VERSION 5.8 ;
BUSBITCHARS "[]" ;
DIVIDERCHAR "/" ;
UNITS
    DATABASE MICRONS 1000 ;
END UNITS

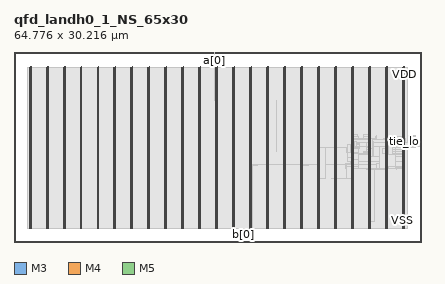
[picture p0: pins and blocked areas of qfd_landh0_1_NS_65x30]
MACRO qfd_landh0_1_NS_65x30
  FOREIGN qfd_landh0_1_NS_65x30 0 0 ;
  CLASS BLOCK ;
  SIZE 64.776 BY 30.216 ;
  PIN a[0]
    DIRECTION INPUT ;
    USE SIGNAL ;
    PORT
      LAYER M3 ;
        RECT  31.86 30.179 31.878 30.216 ;
    END
  END a[0]
  PIN b[0]
    DIRECTION OUTPUT ;
    USE SIGNAL ;
    PORT
      LAYER M3 ;
        RECT  36.54 0 36.558 0.037 ;
    END
  END b[0]
  PIN ck
    DIRECTION INPUT ;
    USE SIGNAL ;
    PORT
      LAYER M4 ;
        RECT  64.692 15.12 64.776 15.144 ;
    END
  END ck
  PIN ck_s
    DIRECTION INPUT ;
    USE SIGNAL ;
    PORT
      LAYER M4 ;
        RECT  64.692 15.216 64.776 15.24 ;
    END
  END ck_s
  PIN en
    DIRECTION INPUT ;
    USE SIGNAL ;
    PORT
      LAYER M4 ;
        RECT  64.692 15.312 64.776 15.336 ;
    END
  END en
  PIN fault
    DIRECTION OUTPUT ;
    USE SIGNAL ;
    PORT
      LAYER M4 ;
        RECT  64.692 15.408 64.776 15.432 ;
    END
  END fault
  PIN k0
    DIRECTION INPUT ;
    USE SIGNAL ;
    PORT
      LAYER M4 ;
        RECT  64.692 15.504 64.776 15.528 ;
    END
  END k0
  PIN k1
    DIRECTION INPUT ;
    USE SIGNAL ;
    PORT
      LAYER M4 ;
        RECT  64.692 15.6 64.776 15.624 ;
    END
  END k1
  PIN k2
    DIRECTION INPUT ;
    USE SIGNAL ;
    PORT
      LAYER M4 ;
        RECT  64.692 15.696 64.776 15.72 ;
    END
  END k2
  PIN rs
    DIRECTION INPUT ;
    USE SIGNAL ;
    PORT
      LAYER M4 ;
        RECT  64.692 15.792 64.776 15.816 ;
    END
  END rs
  PIN tie_hi
    DIRECTION OUTPUT ;
    USE SIGNAL ;
    PORT
      LAYER M4 ;
        RECT  64.692 15.888 64.776 15.912 ;
    END
  END tie_hi
  PIN tie_lo
    DIRECTION OUTPUT ;
    USE SIGNAL ;
    PORT
      LAYER M4 ;
        RECT  64.692 15.984 64.776 16.008 ;
    END
  END tie_lo
  PIN VDD
    DIRECTION INOUT ;
    USE POWER ;
    PORT
      LAYER M5 ;
        RECT  61.992 2.151 62.112 27.833 ;
        RECT  59.292 2.151 59.412 27.833 ;
        RECT  56.592 2.151 56.712 27.833 ;
        RECT  53.892 2.151 54.012 27.833 ;
        RECT  51.192 2.151 51.312 27.833 ;
        RECT  48.492 2.151 48.612 27.833 ;
        RECT  45.792 2.151 45.912 27.833 ;
        RECT  43.092 2.151 43.212 27.833 ;
        RECT  40.392 2.151 40.512 27.833 ;
        RECT  37.692 2.151 37.812 27.833 ;
        RECT  34.992 2.151 35.112 27.833 ;
        RECT  32.292 2.151 32.412 27.833 ;
        RECT  29.592 2.151 29.712 27.833 ;
        RECT  26.892 2.151 27.012 27.833 ;
        RECT  24.192 2.151 24.312 27.833 ;
        RECT  21.492 2.151 21.612 27.833 ;
        RECT  18.792 2.151 18.912 27.833 ;
        RECT  16.092 2.151 16.212 27.833 ;
        RECT  13.392 2.151 13.512 27.833 ;
        RECT  10.692 2.151 10.812 27.833 ;
        RECT  7.992 2.151 8.112 27.833 ;
        RECT  5.292 2.151 5.412 27.833 ;
        RECT  2.592 2.151 2.712 27.833 ;
    END
  END VDD
  PIN VSS
    DIRECTION INOUT ;
    USE GROUND ;
    PORT
      LAYER M5 ;
        RECT  61.8 2.137 61.92 27.819 ;
        RECT  59.1 2.137 59.22 27.819 ;
        RECT  56.4 2.137 56.52 27.819 ;
        RECT  53.7 2.137 53.82 27.819 ;
        RECT  51 2.137 51.12 27.819 ;
        RECT  48.3 2.137 48.42 27.819 ;
        RECT  45.6 2.137 45.72 27.819 ;
        RECT  42.9 2.137 43.02 27.819 ;
        RECT  40.2 2.137 40.32 27.819 ;
        RECT  37.5 2.137 37.62 27.819 ;
        RECT  34.8 2.137 34.92 27.819 ;
        RECT  32.1 2.137 32.22 27.819 ;
        RECT  29.4 2.137 29.52 27.819 ;
        RECT  26.7 2.137 26.82 27.819 ;
        RECT  24 2.137 24.12 27.819 ;
        RECT  21.3 2.137 21.42 27.819 ;
        RECT  18.6 2.137 18.72 27.819 ;
        RECT  15.9 2.137 16.02 27.819 ;
        RECT  13.2 2.137 13.32 27.819 ;
        RECT  10.5 2.137 10.62 27.819 ;
        RECT  7.8 2.137 7.92 27.819 ;
        RECT  5.1 2.137 5.22 27.819 ;
        RECT  2.4 2.137 2.52 27.819 ;
    END
  END VSS
  OBS
    LAYER RVTN ;
     RECT  2.16 2.16 62.586 2.295 ;
     RECT  2.16 2.565 62.586 2.835 ;
     RECT  2.16 3.105 62.586 3.375 ;
     RECT  2.16 3.645 62.586 3.915 ;
     RECT  2.16 4.185 62.586 4.455 ;
     RECT  2.16 4.725 62.586 4.995 ;
     RECT  2.16 5.265 62.586 5.535 ;
     RECT  2.16 5.805 62.586 6.075 ;
     RECT  2.16 6.345 62.586 6.615 ;
     RECT  2.16 6.885 62.586 7.155 ;
     RECT  2.16 7.425 62.586 7.695 ;
     RECT  2.16 7.965 62.586 8.235 ;
     RECT  2.16 8.505 62.586 8.775 ;
     RECT  2.16 9.045 62.586 9.315 ;
     RECT  2.16 9.585 62.586 9.855 ;
     RECT  2.16 10.125 62.586 10.395 ;
     RECT  2.16 10.665 62.586 10.935 ;
     RECT  2.16 11.205 62.586 11.475 ;
     RECT  2.16 11.745 62.586 12.015 ;
     RECT  2.16 12.285 62.586 12.555 ;
     RECT  2.16 12.825 62.586 13.095 ;
     RECT  2.16 13.365 62.586 13.635 ;
     RECT  2.16 13.905 62.586 14.175 ;
     RECT  2.16 14.445 62.586 14.715 ;
     RECT  2.16 14.985 62.586 15.255 ;
     RECT  2.16 15.525 62.586 15.795 ;
     RECT  2.16 16.065 62.586 16.335 ;
     RECT  2.16 16.605 62.586 16.875 ;
     RECT  2.16 17.145 62.586 17.415 ;
     RECT  2.16 17.685 62.586 17.955 ;
     RECT  2.16 18.225 62.586 18.495 ;
     RECT  2.16 18.765 62.586 19.035 ;
     RECT  2.16 19.305 62.586 19.575 ;
     RECT  2.16 19.845 62.586 20.115 ;
     RECT  2.16 20.385 62.586 20.655 ;
     RECT  2.16 20.925 62.586 21.195 ;
     RECT  2.16 21.465 62.586 21.735 ;
     RECT  2.16 22.005 62.586 22.275 ;
     RECT  2.16 22.545 62.586 22.815 ;
     RECT  2.16 23.085 62.586 23.355 ;
     RECT  2.16 23.625 62.586 23.895 ;
     RECT  2.16 24.165 62.586 24.435 ;
     RECT  2.16 24.705 62.586 24.975 ;
     RECT  2.16 25.245 62.586 25.515 ;
     RECT  2.16 25.785 62.586 26.055 ;
     RECT  2.16 26.325 62.586 26.595 ;
     RECT  2.16 26.865 62.586 27.135 ;
     RECT  2.16 27.405 62.586 27.675 ;
    LAYER RVTP ;
     RECT  2.16 2.295 62.586 2.565 ;
     RECT  2.16 2.835 62.586 3.105 ;
     RECT  2.16 3.375 62.586 3.645 ;
     RECT  2.16 3.915 62.586 4.185 ;
     RECT  2.16 4.455 62.586 4.725 ;
     RECT  2.16 4.995 62.586 5.265 ;
     RECT  2.16 5.535 62.586 5.805 ;
     RECT  2.16 6.075 62.586 6.345 ;
     RECT  2.16 6.615 62.586 6.885 ;
     RECT  2.16 7.155 62.586 7.425 ;
     RECT  2.16 7.695 62.586 7.965 ;
     RECT  2.16 8.235 62.586 8.505 ;
     RECT  2.16 8.775 62.586 9.045 ;
     RECT  2.16 9.315 62.586 9.585 ;
     RECT  2.16 9.855 62.586 10.125 ;
     RECT  2.16 10.395 62.586 10.665 ;
     RECT  2.16 10.935 62.586 11.205 ;
     RECT  2.16 11.475 62.586 11.745 ;
     RECT  2.16 12.015 62.586 12.285 ;
     RECT  2.16 12.555 62.586 12.825 ;
     RECT  2.16 13.095 62.586 13.365 ;
     RECT  2.16 13.635 62.586 13.905 ;
     RECT  2.16 14.175 62.586 14.445 ;
     RECT  2.16 14.715 62.586 14.985 ;
     RECT  2.16 15.255 62.586 15.525 ;
     RECT  2.16 15.795 62.586 16.065 ;
     RECT  2.16 16.335 62.586 16.605 ;
     RECT  2.16 16.875 62.586 17.145 ;
     RECT  2.16 17.415 62.586 17.685 ;
     RECT  2.16 17.955 62.586 18.225 ;
     RECT  2.16 18.495 62.586 18.765 ;
     RECT  2.16 19.035 62.586 19.305 ;
     RECT  2.16 19.575 62.586 19.845 ;
     RECT  2.16 20.115 62.586 20.385 ;
     RECT  2.16 20.655 62.586 20.925 ;
     RECT  2.16 21.195 62.586 21.465 ;
     RECT  2.16 21.735 62.586 22.005 ;
     RECT  2.16 22.275 62.586 22.545 ;
     RECT  2.16 22.815 62.586 23.085 ;
     RECT  2.16 23.355 62.586 23.625 ;
     RECT  2.16 23.895 62.586 24.165 ;
     RECT  2.16 24.435 62.586 24.705 ;
     RECT  2.16 24.975 62.586 25.245 ;
     RECT  2.16 25.515 62.586 25.785 ;
     RECT  2.16 26.055 62.586 26.325 ;
     RECT  2.16 26.595 62.586 26.865 ;
     RECT  2.16 27.135 62.586 27.405 ;
     RECT  2.16 27.675 62.586 27.81 ;
    LAYER M1 ;
     RECT  2.16 2.151 62.586 27.819 ;
    LAYER M2 ;
     RECT  36.535 0.531 37.859 0.549 ;
     RECT  2.16 2.151 62.586 27.819 ;
     RECT  62.586 14.958 63.311 16.092 ;
     RECT  63.311 14.958 63.347 16.02 ;
     RECT  63.347 14.958 63.887 15.552 ;
     RECT  62.586 16.848 63.887 16.866 ;
     RECT  63.887 14.958 63.923 14.976 ;
    LAYER M3 ;
     RECT  36.54 0.012 36.558 0.554 ;
     RECT  37.836 0.526 37.854 2.143 ;
     RECT  2.415 2.143 2.505 2.413 ;
     RECT  5.115 2.143 5.205 2.413 ;
     RECT  7.815 2.143 7.905 2.413 ;
     RECT  10.515 2.143 10.605 2.413 ;
     RECT  13.215 2.143 13.305 2.413 ;
     RECT  15.915 2.143 16.005 2.413 ;
     RECT  18.615 2.143 18.705 2.413 ;
     RECT  21.315 2.143 21.405 2.413 ;
     RECT  24.015 2.143 24.105 2.413 ;
     RECT  26.715 2.143 26.805 2.413 ;
     RECT  29.415 2.143 29.505 2.413 ;
     RECT  32.115 2.143 32.205 2.413 ;
     RECT  34.815 2.143 34.905 2.413 ;
     RECT  40.215 2.143 40.305 2.413 ;
     RECT  42.915 2.143 43.005 2.413 ;
     RECT  45.615 2.143 45.705 2.413 ;
     RECT  48.315 2.143 48.405 2.413 ;
     RECT  51.015 2.143 51.105 2.413 ;
     RECT  53.715 2.143 53.805 2.413 ;
     RECT  56.415 2.143 56.505 2.413 ;
     RECT  59.115 2.143 59.205 2.413 ;
     RECT  61.815 2.143 61.905 2.413 ;
     RECT  38.844 3.181 38.862 3.299 ;
     RECT  56.415 2.413 56.697 3.307 ;
     RECT  37.515 2.143 37.854 3.343 ;
     RECT  37.515 3.343 37.89 3.389 ;
     RECT  51.015 2.413 51.297 10.021 ;
     RECT  50.544 10.021 51.297 10.121 ;
     RECT  49.428 10.165 49.446 10.205 ;
     RECT  59.115 2.413 59.397 11.479 ;
     RECT  56.415 3.307 57.402 11.515 ;
     RECT  56.088 11.515 57.402 11.551 ;
     RECT  58.14 11.479 59.397 11.551 ;
     RECT  53.715 2.413 53.997 11.641 ;
     RECT  60.804 11.479 60.822 11.641 ;
     RECT  53.715 11.641 54.234 11.659 ;
     RECT  56.088 11.551 59.397 11.677 ;
     RECT  60.588 11.641 60.822 11.677 ;
     RECT  61.815 2.413 62.097 11.677 ;
     RECT  60.588 11.677 62.097 11.713 ;
     RECT  55.944 11.677 59.634 11.749 ;
     RECT  60.444 11.713 62.097 11.749 ;
     RECT  53.1 11.659 54.234 11.785 ;
     RECT  55.944 11.749 62.097 11.785 ;
     RECT  53.1 11.785 54.666 11.821 ;
     RECT  55.548 11.785 62.097 11.821 ;
     RECT  53.1 11.821 62.097 11.975 ;
     RECT  45.615 2.413 45.897 12.187 ;
     RECT  52.776 12.235 52.794 12.283 ;
     RECT  38.772 12.187 38.79 12.317 ;
     RECT  45.615 12.187 45.99 12.317 ;
     RECT  46.764 12.187 46.782 12.317 ;
     RECT  52.668 12.283 52.794 12.413 ;
     RECT  53.568 11.975 62.097 12.865 ;
     RECT  53.064 12.865 62.097 13.981 ;
     RECT  52.992 13.981 62.097 14.009 ;
     RECT  52.992 14.009 54.774 14.203 ;
     RECT  52.848 14.203 54.774 14.243 ;
     RECT  55.584 14.009 62.097 14.405 ;
     RECT  56.016 14.405 62.097 14.755 ;
     RECT  53.532 14.243 54.774 14.791 ;
     RECT  53.532 14.791 54.954 15.019 ;
     RECT  56.016 14.755 62.37 15.053 ;
     RECT  63.9 14.953 63.918 15.223 ;
     RECT  63.864 15.223 63.918 15.295 ;
     RECT  53.028 15.019 54.954 15.449 ;
     RECT  53.604 15.449 54.954 15.629 ;
     RECT  63.288 15.295 63.918 15.725 ;
     RECT  56.052 15.053 62.37 15.787 ;
     RECT  63.288 15.725 63.882 15.787 ;
     RECT  53.715 15.629 54.954 15.799 ;
     RECT  56.052 15.787 63.882 15.799 ;
     RECT  53.715 15.799 63.882 15.863 ;
     RECT  63.288 15.863 63.882 16.097 ;
     RECT  53.715 15.863 62.298 16.295 ;
     RECT  58.716 16.295 62.298 16.403 ;
     RECT  53.715 16.295 57.654 16.529 ;
     RECT  59.115 16.403 62.298 16.529 ;
     RECT  59.115 16.529 62.097 16.601 ;
     RECT  60.66 16.601 62.097 16.709 ;
     RECT  53.715 16.529 54.81 16.799 ;
     RECT  55.584 16.529 56.697 16.799 ;
     RECT  57.492 16.529 57.654 16.799 ;
     RECT  60.66 16.709 60.678 16.799 ;
     RECT  63.864 16.097 63.882 16.871 ;
     RECT  57.636 16.799 57.654 16.943 ;
     RECT  53.715 16.799 54.666 17.069 ;
     RECT  55.62 16.799 56.697 17.069 ;
     RECT  41.724 14.377 41.742 22.469 ;
     RECT  32.115 2.413 32.397 22.477 ;
     RECT  2.415 2.413 2.697 27.557 ;
     RECT  5.115 2.413 5.397 27.557 ;
     RECT  7.815 2.413 8.097 27.557 ;
     RECT  10.515 2.413 10.797 27.557 ;
     RECT  13.215 2.413 13.497 27.557 ;
     RECT  15.915 2.413 16.197 27.557 ;
     RECT  18.615 2.413 18.897 27.557 ;
     RECT  21.315 2.413 21.597 27.557 ;
     RECT  24.015 2.413 24.297 27.557 ;
     RECT  26.715 2.413 26.997 27.557 ;
     RECT  29.415 2.413 29.697 27.557 ;
     RECT  34.815 2.413 35.097 27.557 ;
     RECT  37.515 3.389 37.797 27.557 ;
     RECT  40.215 2.413 40.497 27.557 ;
     RECT  42.915 2.413 43.197 27.557 ;
     RECT  45.615 12.317 45.897 27.557 ;
     RECT  48.315 2.413 48.597 27.557 ;
     RECT  51.015 10.121 51.297 27.557 ;
     RECT  53.715 17.069 53.997 27.557 ;
     RECT  56.415 17.069 56.697 27.557 ;
     RECT  59.115 16.601 59.397 27.557 ;
     RECT  61.815 16.709 62.097 27.557 ;
     RECT  2.607 27.557 2.697 27.827 ;
     RECT  5.307 27.557 5.397 27.827 ;
     RECT  8.007 27.557 8.097 27.827 ;
     RECT  10.707 27.557 10.797 27.827 ;
     RECT  13.407 27.557 13.497 27.827 ;
     RECT  16.107 27.557 16.197 27.827 ;
     RECT  18.807 27.557 18.897 27.827 ;
     RECT  21.507 27.557 21.597 27.827 ;
     RECT  24.207 27.557 24.297 27.827 ;
     RECT  26.907 27.557 26.997 27.827 ;
     RECT  29.607 27.557 29.697 27.827 ;
     RECT  31.86 22.477 32.397 27.827 ;
     RECT  35.007 27.557 35.097 27.827 ;
     RECT  37.707 27.557 37.797 27.827 ;
     RECT  40.407 27.557 40.497 27.827 ;
     RECT  43.107 27.557 43.197 27.827 ;
     RECT  45.807 27.557 45.897 27.827 ;
     RECT  48.507 27.557 48.597 27.827 ;
     RECT  51.207 27.557 51.297 27.827 ;
     RECT  53.907 27.557 53.997 27.827 ;
     RECT  56.607 27.557 56.697 27.827 ;
     RECT  59.307 27.557 59.397 27.827 ;
     RECT  62.007 27.557 62.097 27.827 ;
     RECT  31.86 27.827 31.878 30.204 ;
    LAYER M4 ;
     RECT  2.408 2.148 2.512 27.552 ;
     RECT  2.512 2.418 2.6 27.552 ;
     RECT  2.6 2.418 2.704 27.822 ;
     RECT  5.108 2.148 5.212 27.552 ;
     RECT  5.212 2.418 5.3 27.552 ;
     RECT  5.3 2.418 5.404 27.822 ;
     RECT  7.808 2.148 7.912 27.552 ;
     RECT  7.912 2.418 8 27.552 ;
     RECT  8 2.418 8.104 27.822 ;
     RECT  10.508 2.148 10.612 27.552 ;
     RECT  10.612 2.418 10.7 27.552 ;
     RECT  10.7 2.418 10.804 27.822 ;
     RECT  13.208 2.148 13.312 27.552 ;
     RECT  13.312 2.418 13.4 27.552 ;
     RECT  13.4 2.418 13.504 27.822 ;
     RECT  15.908 2.148 16.012 27.552 ;
     RECT  16.012 2.418 16.1 27.552 ;
     RECT  16.1 2.418 16.204 27.822 ;
     RECT  18.608 2.148 18.712 27.552 ;
     RECT  18.712 2.418 18.8 27.552 ;
     RECT  18.8 2.418 18.904 27.822 ;
     RECT  21.308 2.148 21.412 27.552 ;
     RECT  21.412 2.418 21.5 27.552 ;
     RECT  21.5 2.418 21.604 27.822 ;
     RECT  24.008 2.148 24.112 27.552 ;
     RECT  24.112 2.418 24.2 27.552 ;
     RECT  24.2 2.418 24.304 27.822 ;
     RECT  26.708 2.148 26.812 27.552 ;
     RECT  26.812 2.418 26.9 27.552 ;
     RECT  26.9 2.418 27.004 27.822 ;
     RECT  29.408 2.148 29.512 27.552 ;
     RECT  29.512 2.418 29.6 27.552 ;
     RECT  29.6 2.418 29.704 27.822 ;
     RECT  32.108 2.148 32.212 27.552 ;
     RECT  32.212 2.418 32.3 27.552 ;
     RECT  32.3 2.418 32.404 27.822 ;
     RECT  34.808 2.148 34.912 27.552 ;
     RECT  34.912 2.418 35 27.552 ;
     RECT  35 2.418 35.104 27.822 ;
     RECT  37.508 2.148 37.612 27.552 ;
     RECT  37.612 2.418 37.7 27.552 ;
     RECT  37.7 2.418 37.804 27.822 ;
     RECT  37.804 3.36 37.955 3.384 ;
     RECT  37.804 12.192 38.801 12.312 ;
     RECT  38.801 12.288 40.208 12.312 ;
     RECT  40.208 2.148 40.312 27.552 ;
     RECT  40.312 2.418 40.4 27.552 ;
     RECT  40.4 2.418 40.504 27.822 ;
     RECT  40.504 12.288 42.908 12.312 ;
     RECT  42.908 2.148 43.012 27.552 ;
     RECT  43.012 2.418 43.1 27.552 ;
     RECT  43.1 2.418 43.204 27.822 ;
     RECT  43.204 12.288 45.608 12.312 ;
     RECT  45.608 2.148 45.712 27.552 ;
     RECT  45.712 2.418 45.8 27.552 ;
     RECT  45.8 2.418 45.904 27.822 ;
     RECT  45.904 12.192 46.793 12.312 ;
     RECT  46.793 12.288 48.308 12.312 ;
     RECT  48.308 2.148 48.412 27.552 ;
     RECT  48.412 2.418 48.5 27.552 ;
     RECT  48.5 2.418 48.604 27.822 ;
     RECT  48.604 10.176 49.475 10.2 ;
     RECT  50.677 10.08 51.008 10.104 ;
     RECT  48.604 12.288 51.008 12.312 ;
     RECT  48.604 15.024 51.008 15.048 ;
     RECT  51.008 2.148 51.112 27.552 ;
     RECT  51.112 2.418 51.2 27.552 ;
     RECT  51.2 2.418 51.304 27.822 ;
     RECT  51.304 12.288 52.657 12.312 ;
     RECT  52.657 12.288 52.748 12.408 ;
     RECT  52.748 12.24 52.789 12.408 ;
     RECT  51.304 15.024 52.837 15.048 ;
     RECT  52.837 14.208 53.017 15.048 ;
     RECT  53.017 14.208 53.029 15.432 ;
     RECT  51.304 10.08 53.708 10.104 ;
     RECT  52.789 11.664 53.708 12.408 ;
     RECT  53.029 13.44 53.708 15.432 ;
     RECT  53.708 2.148 53.812 27.552 ;
     RECT  53.812 2.418 53.9 27.552 ;
     RECT  53.9 2.418 54.004 27.822 ;
     RECT  54.004 15.216 54.461 16.008 ;
     RECT  54.004 11.664 54.793 14.088 ;
     RECT  54.793 14.064 55.645 14.088 ;
     RECT  54.793 11.664 56.408 12.312 ;
     RECT  55.645 14.064 56.408 14.184 ;
     RECT  54.461 15.216 56.408 15.24 ;
     RECT  56.408 2.148 56.512 27.552 ;
     RECT  56.512 2.418 56.6 27.552 ;
     RECT  56.6 2.418 56.704 27.822 ;
     RECT  56.704 13.536 57.011 16.488 ;
     RECT  57.011 13.536 57.197 15.96 ;
     RECT  56.704 11.664 57.697 12.312 ;
     RECT  57.697 11.664 58.057 12.552 ;
     RECT  57.197 13.536 58.057 15.24 ;
     RECT  58.057 11.664 59.065 15.24 ;
     RECT  59.065 11.664 59.108 16.008 ;
     RECT  59.108 2.148 59.212 27.552 ;
     RECT  59.212 2.418 59.3 27.552 ;
     RECT  59.3 2.418 59.404 27.822 ;
     RECT  59.404 11.664 59.555 12.312 ;
     RECT  59.404 13.92 59.555 16.584 ;
     RECT  59.555 13.92 60.221 16.008 ;
     RECT  60.221 13.92 60.397 13.944 ;
     RECT  60.397 13.632 60.437 13.944 ;
     RECT  59.555 11.664 60.62 11.976 ;
     RECT  60.221 15.024 60.661 16.008 ;
     RECT  60.62 11.664 60.707 12.552 ;
     RECT  60.661 15.024 60.707 16.488 ;
     RECT  60.437 13.632 61.808 13.656 ;
     RECT  60.707 15.024 61.808 15.24 ;
     RECT  60.707 16.464 61.808 16.488 ;
     RECT  61.808 2.148 61.912 27.552 ;
     RECT  61.912 2.418 62 27.552 ;
     RECT  62 2.418 62.104 27.822 ;
     RECT  62.104 15.024 62.129 15.816 ;
     RECT  62.129 15.12 63.277 15.816 ;
     RECT  63.277 15.12 63.313 15.912 ;
     RECT  63.313 15.12 64.716 16.008 ;
    LAYER M5 ;
     RECT  2.4 2.137 2.52 2.151 ;
     RECT  5.1 2.137 5.22 2.151 ;
     RECT  7.8 2.137 7.92 2.151 ;
     RECT  10.5 2.137 10.62 2.151 ;
     RECT  13.2 2.137 13.32 2.151 ;
     RECT  15.9 2.137 16.02 2.151 ;
     RECT  18.6 2.137 18.72 2.151 ;
     RECT  21.3 2.137 21.42 2.151 ;
     RECT  24 2.137 24.12 2.151 ;
     RECT  26.7 2.137 26.82 2.151 ;
     RECT  29.4 2.137 29.52 2.151 ;
     RECT  32.1 2.137 32.22 2.151 ;
     RECT  34.8 2.137 34.92 2.151 ;
     RECT  37.5 2.137 37.62 2.151 ;
     RECT  40.2 2.137 40.32 2.151 ;
     RECT  42.9 2.137 43.02 2.151 ;
     RECT  45.6 2.137 45.72 2.151 ;
     RECT  48.3 2.137 48.42 2.151 ;
     RECT  51 2.137 51.12 2.151 ;
     RECT  53.7 2.137 53.82 2.151 ;
     RECT  56.4 2.137 56.52 2.151 ;
     RECT  59.1 2.137 59.22 2.151 ;
     RECT  61.8 2.137 61.92 2.151 ;
     RECT  37.5 2.151 37.812 3.349 ;
     RECT  53.7 2.151 54.012 10.069 ;
     RECT  48.3 2.151 48.612 10.165 ;
     RECT  52.8 10.069 54.012 11.941 ;
     RECT  59.1 2.151 59.412 11.941 ;
     RECT  60.672 11.653 60.696 11.941 ;
     RECT  37.5 3.349 37.944 12.227 ;
     RECT  52.8 11.941 54.744 12.275 ;
     RECT  53.7 12.275 54.744 13.139 ;
     RECT  53.7 13.139 54.012 13.429 ;
     RECT  59.1 11.941 60.696 13.955 ;
     RECT  59.1 13.955 59.544 14.005 ;
     RECT  53.04 13.429 54.012 14.243 ;
     RECT  56.4 2.151 56.712 14.869 ;
     RECT  58.656 14.005 59.544 14.915 ;
     RECT  48.3 10.165 49.464 15.059 ;
     RECT  53.568 14.243 54.012 15.301 ;
     RECT  53.568 15.301 54.12 15.443 ;
     RECT  53.7 15.443 54.12 16.019 ;
     RECT  56.4 14.869 57 16.499 ;
     RECT  60.672 13.955 60.696 16.499 ;
     RECT  59.1 14.915 59.544 16.595 ;
     RECT  2.4 2.151 2.712 27.819 ;
     RECT  5.1 2.151 5.412 27.819 ;
     RECT  7.8 2.151 8.112 27.819 ;
     RECT  10.5 2.151 10.812 27.819 ;
     RECT  13.2 2.151 13.512 27.819 ;
     RECT  15.9 2.151 16.212 27.819 ;
     RECT  18.6 2.151 18.912 27.819 ;
     RECT  21.3 2.151 21.612 27.819 ;
     RECT  24 2.151 24.312 27.819 ;
     RECT  26.7 2.151 27.012 27.819 ;
     RECT  29.4 2.151 29.712 27.819 ;
     RECT  32.1 2.151 32.412 27.819 ;
     RECT  34.8 2.151 35.112 27.819 ;
     RECT  37.5 12.227 37.812 27.819 ;
     RECT  40.2 2.151 40.512 27.819 ;
     RECT  42.9 2.151 43.212 27.819 ;
     RECT  45.6 2.151 45.912 27.819 ;
     RECT  48.3 15.059 48.612 27.819 ;
     RECT  51 2.151 51.312 27.819 ;
     RECT  53.7 16.019 54.012 27.819 ;
     RECT  56.4 16.499 56.712 27.819 ;
     RECT  59.1 16.595 59.412 27.819 ;
     RECT  61.8 2.151 62.112 27.819 ;
     RECT  2.592 27.819 2.712 27.833 ;
     RECT  5.292 27.819 5.412 27.833 ;
     RECT  7.992 27.819 8.112 27.833 ;
     RECT  10.692 27.819 10.812 27.833 ;
     RECT  13.392 27.819 13.512 27.833 ;
     RECT  16.092 27.819 16.212 27.833 ;
     RECT  18.792 27.819 18.912 27.833 ;
     RECT  21.492 27.819 21.612 27.833 ;
     RECT  24.192 27.819 24.312 27.833 ;
     RECT  26.892 27.819 27.012 27.833 ;
     RECT  29.592 27.819 29.712 27.833 ;
     RECT  32.292 27.819 32.412 27.833 ;
     RECT  34.992 27.819 35.112 27.833 ;
     RECT  37.692 27.819 37.812 27.833 ;
     RECT  40.392 27.819 40.512 27.833 ;
     RECT  43.092 27.819 43.212 27.833 ;
     RECT  45.792 27.819 45.912 27.833 ;
     RECT  48.492 27.819 48.612 27.833 ;
     RECT  51.192 27.819 51.312 27.833 ;
     RECT  53.892 27.819 54.012 27.833 ;
     RECT  56.592 27.819 56.712 27.833 ;
     RECT  59.292 27.819 59.412 27.833 ;
     RECT  61.992 27.819 62.112 27.833 ;
  END
END qfd_landh0_1_NS_65x30
END LIBRARY
